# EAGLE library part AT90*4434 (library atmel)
MICROCONTROLLER Low-voltage (LS) 4 Kbytes FLASH 256 bytes SRAM 256 bytes EEPROM UART 8-channel 10 bit ADC

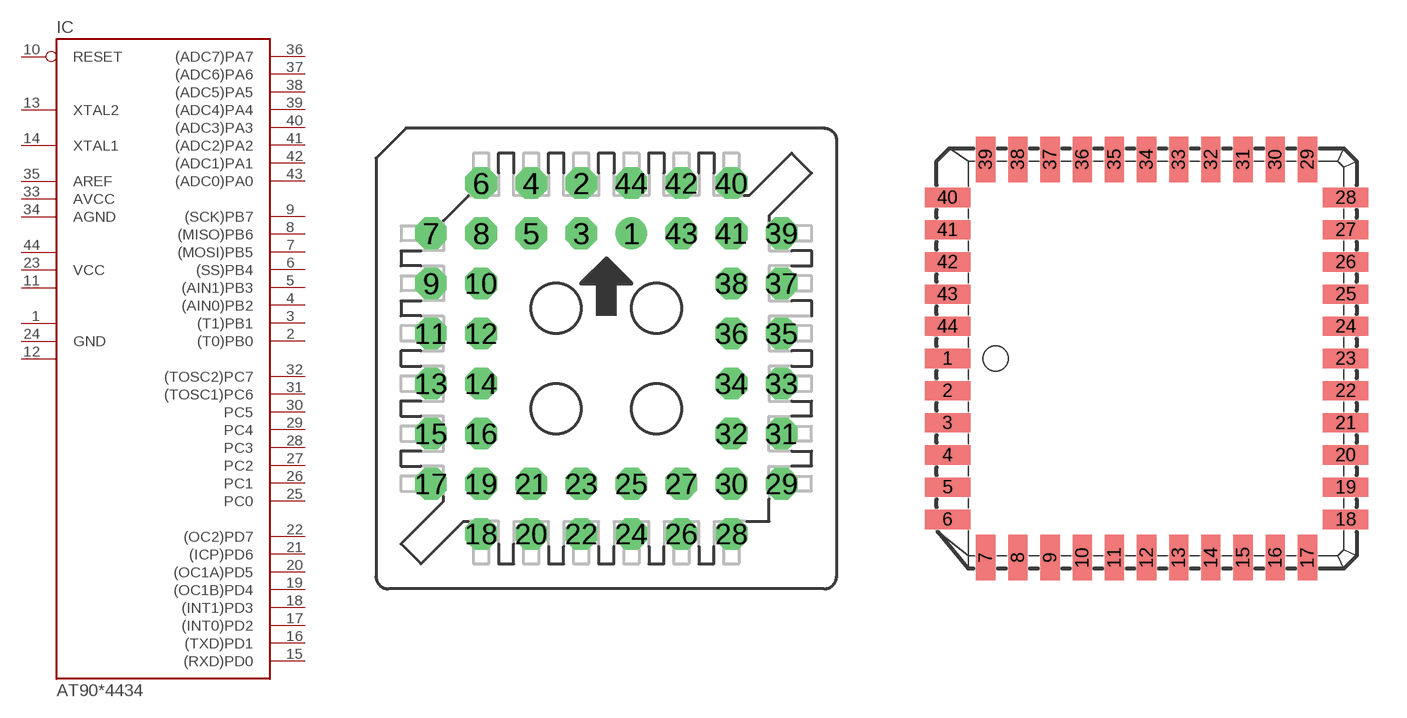
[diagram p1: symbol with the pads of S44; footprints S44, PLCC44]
Designator prefix IC

## AT90LS4434J-S (OC_FARNELL: unknown; OC_NEWARK: unknown), AT90S4434J-S (OC_FARNELL: unknown; OC_NEWARK: unknown)  [S44]
1  GND1  pwr
2  (T0)PB0
3  (T1)PB1
4  (AIN0)PB2
5  (AIN1)PB3
6  (SS)PB4
7  (MOSI)PB5
8  (MISO)PB6
9  (SCK)PB7
10  RESET  in
11  VCC2  pwr
12  GND2  pwr
13  XTAL2
14  XTAL1
15  (RXD)PD0
16  (TXD)PD1
17  (INT0)PD2
18  (INT1)PD3
19  (OC1B)PD4
20  (OC1A)PD5
21  (ICP)PD6
22  (OC2)PD7
23  VCC  pwr
24  GND  pwr
25  PC0
26  PC1
27  PC2
28  PC3
29  PC4
30  PC5
31  (TOSC1)PC6
32  (TOSC2)PC7
33  AVCC  pwr
34  AGND  pwr
35  AREF  pas
36  (ADC7)PA7
37  (ADC6)PA6
38  (ADC5)PA5
39  (ADC4)PA4
40  (ADC3)PA3
41  (ADC2)PA2
42  (ADC1)PA1
43  (ADC0)PA0
44  VCC1  pwr

## AT90LS4434J (OC_FARNELL: unknown; OC_NEWARK: unknown), AT90S4434J (OC_FARNELL: unknown; OC_NEWARK: unknown)  [PLCC44]
1  GND1  pwr
2  (T0)PB0
3  (T1)PB1
4  (AIN0)PB2
5  (AIN1)PB3
6  (SS)PB4
7  (MOSI)PB5
8  (MISO)PB6
9  (SCK)PB7
10  RESET  in
11  VCC1  pwr
12  GND2  pwr
13  XTAL2
14  XTAL1
15  (RXD)PD0
16  (TXD)PD1
17  (INT0)PD2
18  (INT1)PD3
19  (OC1B)PD4
20  (OC1A)PD5
21  (ICP)PD6
22  (OC2)PD7
23  VCC  pwr
24  GND  pwr
25  PC0
26  PC1
27  PC2
28  PC3
29  PC4
30  PC5
31  (TOSC1)PC6
32  (TOSC2)PC7
33  AVCC  pwr
34  AGND  pwr
35  AREF  pas
36  (ADC7)PA7
37  (ADC6)PA6
38  (ADC5)PA5
39  (ADC4)PA4
40  (ADC3)PA3
41  (ADC2)PA2
42  (ADC1)PA1
43  (ADC0)PA0
44  VCC2  pwr

## AT90LS4434J-SM (OC_FARNELL: unknown; OC_NEWARK: unknown), AT90S4434J-SM (OC_FARNELL: unknown; OC_NEWARK: unknown)  [PLCC-SM44]
Pads as for PLCC44

## AT904434A (OC_FARNELL: unknown; OC_NEWARK: unknown)  [TQFP44]
1  (MOSI)PB5
2  (MISO)PB6
3  (SCK)PB7
4  RESET  in
5  VCC  pwr
6  GND  pwr
7  XTAL2
8  XTAL1
9  (RXD)PD0
10  (TXD)PD1
11  (INT0)PD2
12  (INT1)PD3
13  (OC1B)PD4
14  (OC1A)PD5
15  (ICP)PD6
16  (OC2)PD7
17  VCC1  pwr
18  GND1  pwr
19  PC0
20  PC1
21  PC2
22  PC3
23  PC4
24  PC5
25  (TOSC1)PC6
26  (TOSC2)PC7
27  AVCC  pwr
28  AGND  pwr
29  AREF  pas
30  (ADC7)PA7
31  (ADC6)PA6
32  (ADC5)PA5
33  (ADC4)PA4
34  (ADC3)PA3
35  (ADC2)PA2
36  (ADC1)PA1
37  (ADC0)PA0
38  VCC2  pwr
39  GND2  pwr
40  (T0)PB0
41  (T1)PB1
42  (AIN0)PB2
43  (AIN1)PB3
44  (SS)PB4

## Footprint S44 (pad centres in mm)
Throughhole Plastic J-Leaded Chip Carrier Socket
drill 0.813 pad 1.6 round: 1 1.27,6.35
drill 0.813 pad 1.6 octagon: 2 -1.27,8.89; 3 -1.27,6.35; 4 -3.81,8.89; 5 -3.81,6.35; 6 -6.35,8.89; 7 -8.89,6.35; 8 -6.35,6.35; 9 -8.89,3.81; 10 -6.35,3.81; 11 -8.89,1.27; 12 -6.35,1.27; 13 -8.89,-1.27; 14 -6.35,-1.27; 15 -8.89,-3.81; 16 -6.35,-3.81; 17 -8.89,-6.35; 18 -6.35,-8.89; 19 -6.35,-6.35; 20 -3.81,-8.89; 21 -3.81,-6.35; 22 -1.27,-8.89; 23 -1.27,-6.35; 24 1.27,-8.89; 25 1.27,-6.35; 26 3.81,-8.89; 27 3.81,-6.35; 28 6.35,-8.89; 29 8.89,-6.35; 30 6.35,-6.35; 31 8.89,-3.81; 32 6.35,-3.81; 33 8.89,-1.27; 34 6.35,-1.27; 35 8.89,1.27; 36 6.35,1.27; 37 8.89,3.81; 38 6.35,3.81; 39 8.89,6.35; 40 6.35,8.89; 41 6.35,6.35; 42 3.81,8.89; 43 3.81,6.35; 44 1.27,8.89

## Footprint PLCC44 (pad centres in mm)
Plastic J-Leaded Chip Carrier
smd 1.8 x 0.76: 1 -7.86,0; 2 -7.86,-1.27; 3 -7.86,-2.54; 4 -7.86,-3.81; 5 -7.86,-5.08; 6 -7.86,-6.35; 18 7.86,-6.35; 19 7.86,-5.08; 20 7.86,-3.81; 21 7.86,-2.54; 22 7.86,-1.27; 23 7.86,0; 24 7.86,1.27; 25 7.86,2.54; 26 7.86,3.81; 27 7.86,5.08; 28 7.86,6.35; 40 -7.86,6.35; 41 -7.86,5.08; 42 -7.86,3.81; 43 -7.86,2.54; 44 -7.86,1.27
smd 0.76 x 1.8: 7 -6.35,-7.86; 8 -5.08,-7.86; 9 -3.81,-7.86; 10 -2.54,-7.86; 11 -1.27,-7.86; 12 0,-7.86; 13 1.27,-7.86; 14 2.54,-7.86; 15 3.81,-7.86; 16 5.08,-7.86; 17 6.35,-7.86; 29 6.35,7.86; 30 5.08,7.86; 31 3.81,7.86; 32 2.54,7.86; 33 1.27,7.86; 34 0,7.86; 35 -1.27,7.86; 36 -2.54,7.86; 37 -3.81,7.86; 38 -5.08,7.86; 39 -6.35,7.86

## Footprint PLCC-SM44 (pad centres in mm)
SMD Plastic J-Leaded Chip Carrier Socket
smd 2.591 x 0.66: 1 -8.89,0; 2 -8.89,-1.27; 3 -8.89,-2.54; 4 -8.89,-3.81; 5 -8.89,-5.08; 6 -8.89,-6.35; 18 8.89,-6.35; 19 8.89,-5.08; 20 8.89,-3.81; 21 8.89,-2.54; 22 8.89,-1.27; 23 8.89,0; 24 8.89,1.27; 25 8.89,2.54; 26 8.89,3.81; 27 8.89,5.08; 28 8.89,6.35; 40 -8.89,6.35; 41 -8.89,5.08; 42 -8.89,3.81; 43 -8.89,2.54; 44 -8.89,1.27
smd 0.66 x 2.591: 7 -6.35,-8.89; 8 -5.08,-8.89; 9 -3.81,-8.89; 10 -2.54,-8.89; 11 -1.27,-8.89; 12 0,-8.89; 13 1.27,-8.89; 14 2.54,-8.89; 15 3.81,-8.89; 16 5.08,-8.89; 17 6.35,-8.89; 29 6.35,8.89; 30 5.08,8.89; 31 3.81,8.89; 32 2.54,8.89; 33 1.27,8.89; 34 0,9.017; 35 -1.27,8.89; 36 -2.54,8.89; 37 -3.81,8.89; 38 -5.08,8.89; 39 -6.35,8.89

## Footprint TQFP44 (pad centres in mm)
44-lead Thin Quad Flat Package
smd 1.5 x 0.5: 1 -5.8,4; 2 -5.8,3.2; 3 -5.8,2.4; 4 -5.8,1.6; 5 -5.8,0.8; 6 -5.8,0; 7 -5.8,-0.8; 8 -5.8,-1.6; 9 -5.8,-2.4; 10 -5.8,-3.2; 11 -5.8,-4; 23 5.8,-4; 24 5.8,-3.2; 25 5.8,-2.4; 26 5.8,-1.6; 27 5.8,-0.8; 28 5.8,0; 29 5.8,0.8; 30 5.8,1.6; 31 5.8,2.4; 32 5.8,3.2; 33 5.8,4
smd 0.5 x 1.5: 12 -4,-5.8; 13 -3.2,-5.8; 14 -2.4,-5.8; 15 -1.6,-5.8; 16 -0.8,-5.8; 17 0,-5.8; 18 0.8,-5.8; 19 1.6,-5.8; 20 2.4,-5.8; 21 3.2,-5.8; 22 4,-5.8; 34 4,5.8; 35 3.2,5.8; 36 2.4,5.8; 37 1.6,5.8; 38 0.8,5.8; 39 0,5.8; 40 -0.8,5.8; 41 -1.6,5.8; 42 -2.4,5.8; 43 -3.2,5.8; 44 -4,5.8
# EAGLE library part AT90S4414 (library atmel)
MICROCONTROLLER 4 Kbytes FLASH 256 bytes SRAM 256 bytes EEPROM UART

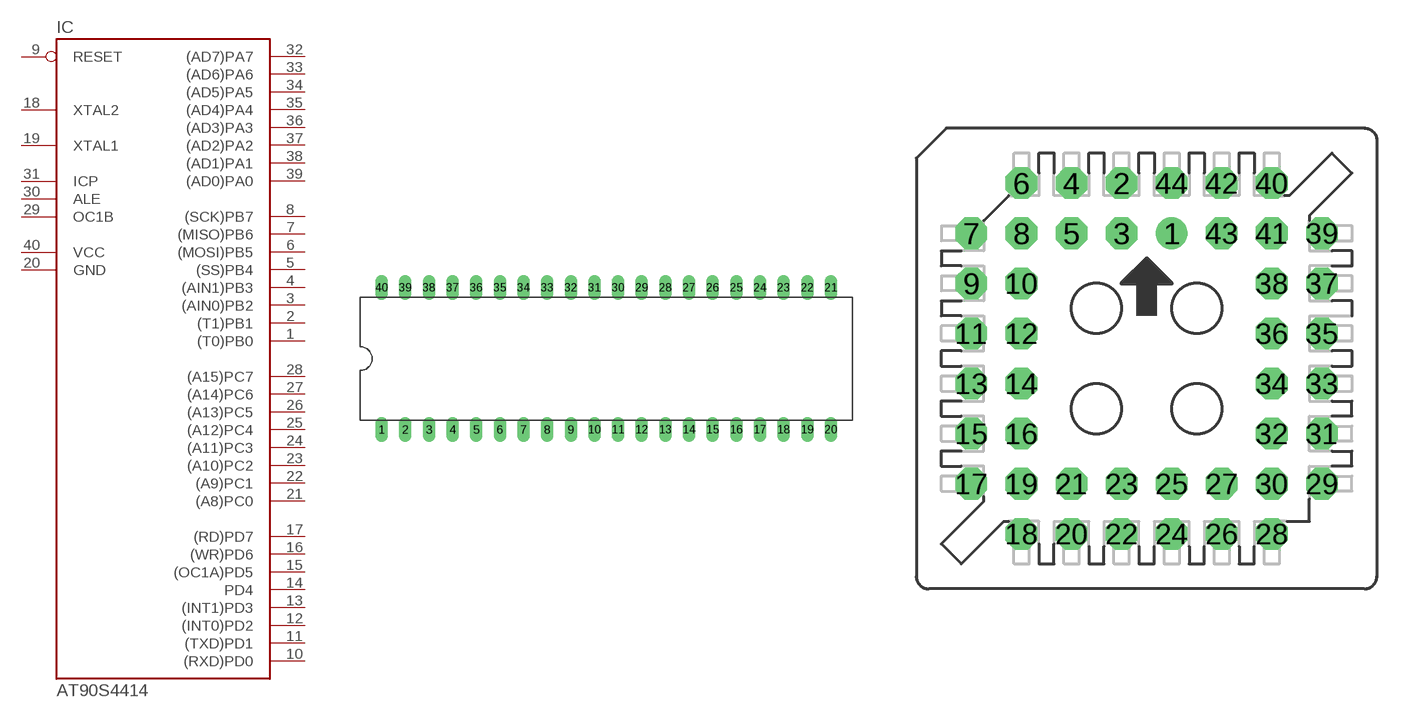
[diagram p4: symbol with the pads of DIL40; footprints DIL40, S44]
Designator prefix IC

## AT90S4414P (OC_FARNELL: unknown; OC_NEWARK: unknown)  [DIL40]
1  (T0)PB0
2  (T1)PB1
3  (AIN0)PB2
4  (AIN1)PB3
5  (SS)PB4
6  (MOSI)PB5
7  (MISO)PB6
8  (SCK)PB7
9  RESET  in
10  (RXD)PD0
11  (TXD)PD1
12  (INT0)PD2
13  (INT1)PD3
14  PD4
15  (OC1A)PD5
16  (WR)PD6
17  (RD)PD7
18  XTAL2
19  XTAL1
20  GND  pwr
21  (A8)PC0
22  (A9)PC1
23  (A10)PC2
24  (A11)PC3
25  (A12)PC4
26  (A13)PC5
27  (A14)PC6
28  (A15)PC7
29  OC1B
30  ALE
31  ICP
32  (AD7)PA7
33  (AD6)PA6
34  (AD5)PA5
35  (AD4)PA4
36  (AD3)PA3
37  (AD2)PA2
38  (AD1)PA1
39  (AD0)PA0
40  VCC  pwr

## AT90S4414J1 (OC_FARNELL: unknown; OC_NEWARK: unknown)  [S44]
2  (T0)PB0
3  (T1)PB1
4  (AIN0)PB2
5  (AIN1)PB3
6  (SS)PB4
7  (MOSI)PB5
8  (MISO)PB6
9  (SCK)PB7
10  RESET  in
11  (RXD)PD0
13  (TXD)PD1
14  (INT0)PD2
15  (INT1)PD3
16  PD4
17  (OC1A)PD5
18  (WR)PD6
19  (RD)PD7
20  XTAL2
21  XTAL1
22  GND  pwr
24  (A8)PC0
25  (A9)PC1
26  (A10)PC2
27  (A11)PC3
28  (A12)PC4
29  (A13)PC5
30  (A14)PC6
31  (A15)PC7
32  OC1B
33  ALE
35  ICP
36  (AD7)PA7
37  (AD6)PA6
38  (AD5)PA5
39  (AD4)PA4
40  (AD3)PA3
41  (AD2)PA2
42  (AD1)PA1
43  (AD0)PA0
44  VCC  pwr

## AT90S4414J2 (OC_FARNELL: unknown; OC_NEWARK: unknown)  [PLCC44]
Pads as for S44

## AT90S4414J3 (OC_FARNELL: unknown; OC_NEWARK: unknown)  [PLCC-SM44]
Pads as for S44

## AT90S4414A (OC_FARNELL: unknown; OC_NEWARK: unknown)  [TQFP44]
1  (MOSI)PB5
2  (MISO)PB6
3  (SCK)PB7
4  RESET  in
5  (RXD)PD0
7  (TXD)PD1
8  (INT0)PD2
9  (INT1)PD3
10  PD4
11  (OC1A)PD5
12  (WR)PD6
13  (RD)PD7
14  XTAL2
15  XTAL1
16  GND  pwr
18  (A8)PC0
19  (A9)PC1
20  (A10)PC2
21  (A11)PC3
22  (A12)PC4
23  (A13)PC5
24  (A14)PC6
25  (A15)PC7
26  OC1B
27  ALE
29  ICP
30  (AD7)PA7
31  (AD6)PA6
32  (AD5)PA5
33  (AD4)PA4
34  (AD3)PA3
35  (AD2)PA2
36  (AD1)PA1
37  (AD0)PA0
38  VCC  pwr
40  (T0)PB0
41  (T1)PB1
42  (AIN0)PB2
43  (AIN1)PB3
44  (SS)PB4

## Footprint DIL40 (pad centres in mm)
Dual In Line
drill 0.813 long: 1 -24.13,-7.62; 2 -21.59,-7.62; 3 -19.05,-7.62; 4 -16.51,-7.62; 5 -13.97,-7.62; 6 -11.43,-7.62; 7 -8.89,-7.62; 8 -6.35,-7.62; 9 -3.81,-7.62; 10 -1.27,-7.62; 11 1.27,-7.62; 12 3.81,-7.62; 13 6.35,-7.62; 14 8.89,-7.62; 15 11.43,-7.62; 16 13.97,-7.62; 17 16.51,-7.62; 18 19.05,-7.62; 19 21.59,-7.62; 20 24.13,-7.62; 21 24.13,7.62; 22 21.59,7.62; 23 19.05,7.62; 24 16.51,7.62; 25 13.97,7.62; 26 11.43,7.62; 27 8.89,7.62; 28 6.35,7.62; 29 3.81,7.62; 30 1.27,7.62; 31 -1.27,7.62; 32 -3.81,7.62; 33 -6.35,7.62; 34 -8.89,7.62; 35 -11.43,7.62; 36 -13.97,7.62; 37 -16.51,7.62; 38 -19.05,7.62; 39 -21.59,7.62; 40 -24.13,7.62

## Footprint S44 (pad centres in mm)
Throughhole Plastic J-Leaded Chip Carrier Socket
drill 0.813 pad 1.6 round: 1 1.27,6.35
drill 0.813 pad 1.6 octagon: 2 -1.27,8.89; 3 -1.27,6.35; 4 -3.81,8.89; 5 -3.81,6.35; 6 -6.35,8.89; 7 -8.89,6.35; 8 -6.35,6.35; 9 -8.89,3.81; 10 -6.35,3.81; 11 -8.89,1.27; 12 -6.35,1.27; 13 -8.89,-1.27; 14 -6.35,-1.27; 15 -8.89,-3.81; 16 -6.35,-3.81; 17 -8.89,-6.35; 18 -6.35,-8.89; 19 -6.35,-6.35; 20 -3.81,-8.89; 21 -3.81,-6.35; 22 -1.27,-8.89; 23 -1.27,-6.35; 24 1.27,-8.89; 25 1.27,-6.35; 26 3.81,-8.89; 27 3.81,-6.35; 28 6.35,-8.89; 29 8.89,-6.35; 30 6.35,-6.35; 31 8.89,-3.81; 32 6.35,-3.81; 33 8.89,-1.27; 34 6.35,-1.27; 35 8.89,1.27; 36 6.35,1.27; 37 8.89,3.81; 38 6.35,3.81; 39 8.89,6.35; 40 6.35,8.89; 41 6.35,6.35; 42 3.81,8.89; 43 3.81,6.35; 44 1.27,8.89

## Footprint PLCC44 (pad centres in mm)
Plastic J-Leaded Chip Carrier
smd 1.8 x 0.76: 1 -7.86,0; 2 -7.86,-1.27; 3 -7.86,-2.54; 4 -7.86,-3.81; 5 -7.86,-5.08; 6 -7.86,-6.35; 18 7.86,-6.35; 19 7.86,-5.08; 20 7.86,-3.81; 21 7.86,-2.54; 22 7.86,-1.27; 23 7.86,0; 24 7.86,1.27; 25 7.86,2.54; 26 7.86,3.81; 27 7.86,5.08; 28 7.86,6.35; 40 -7.86,6.35; 41 -7.86,5.08; 42 -7.86,3.81; 43 -7.86,2.54; 44 -7.86,1.27
smd 0.76 x 1.8: 7 -6.35,-7.86; 8 -5.08,-7.86; 9 -3.81,-7.86; 10 -2.54,-7.86; 11 -1.27,-7.86; 12 0,-7.86; 13 1.27,-7.86; 14 2.54,-7.86; 15 3.81,-7.86; 16 5.08,-7.86; 17 6.35,-7.86; 29 6.35,7.86; 30 5.08,7.86; 31 3.81,7.86; 32 2.54,7.86; 33 1.27,7.86; 34 0,7.86; 35 -1.27,7.86; 36 -2.54,7.86; 37 -3.81,7.86; 38 -5.08,7.86; 39 -6.35,7.86

## Footprint PLCC-SM44 (pad centres in mm)
SMD Plastic J-Leaded Chip Carrier Socket
smd 2.591 x 0.66: 1 -8.89,0; 2 -8.89,-1.27; 3 -8.89,-2.54; 4 -8.89,-3.81; 5 -8.89,-5.08; 6 -8.89,-6.35; 18 8.89,-6.35; 19 8.89,-5.08; 20 8.89,-3.81; 21 8.89,-2.54; 22 8.89,-1.27; 23 8.89,0; 24 8.89,1.27; 25 8.89,2.54; 26 8.89,3.81; 27 8.89,5.08; 28 8.89,6.35; 40 -8.89,6.35; 41 -8.89,5.08; 42 -8.89,3.81; 43 -8.89,2.54; 44 -8.89,1.27
smd 0.66 x 2.591: 7 -6.35,-8.89; 8 -5.08,-8.89; 9 -3.81,-8.89; 10 -2.54,-8.89; 11 -1.27,-8.89; 12 0,-8.89; 13 1.27,-8.89; 14 2.54,-8.89; 15 3.81,-8.89; 16 5.08,-8.89; 17 6.35,-8.89; 29 6.35,8.89; 30 5.08,8.89; 31 3.81,8.89; 32 2.54,8.89; 33 1.27,8.89; 34 0,9.017; 35 -1.27,8.89; 36 -2.54,8.89; 37 -3.81,8.89; 38 -5.08,8.89; 39 -6.35,8.89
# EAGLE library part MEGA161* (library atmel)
MICROCONTROLLER 16 Kbytes FLASH 512 bytes EEPROM 1 Kbytes SRAM dual UART hardware multiplier Source: avr.lbr

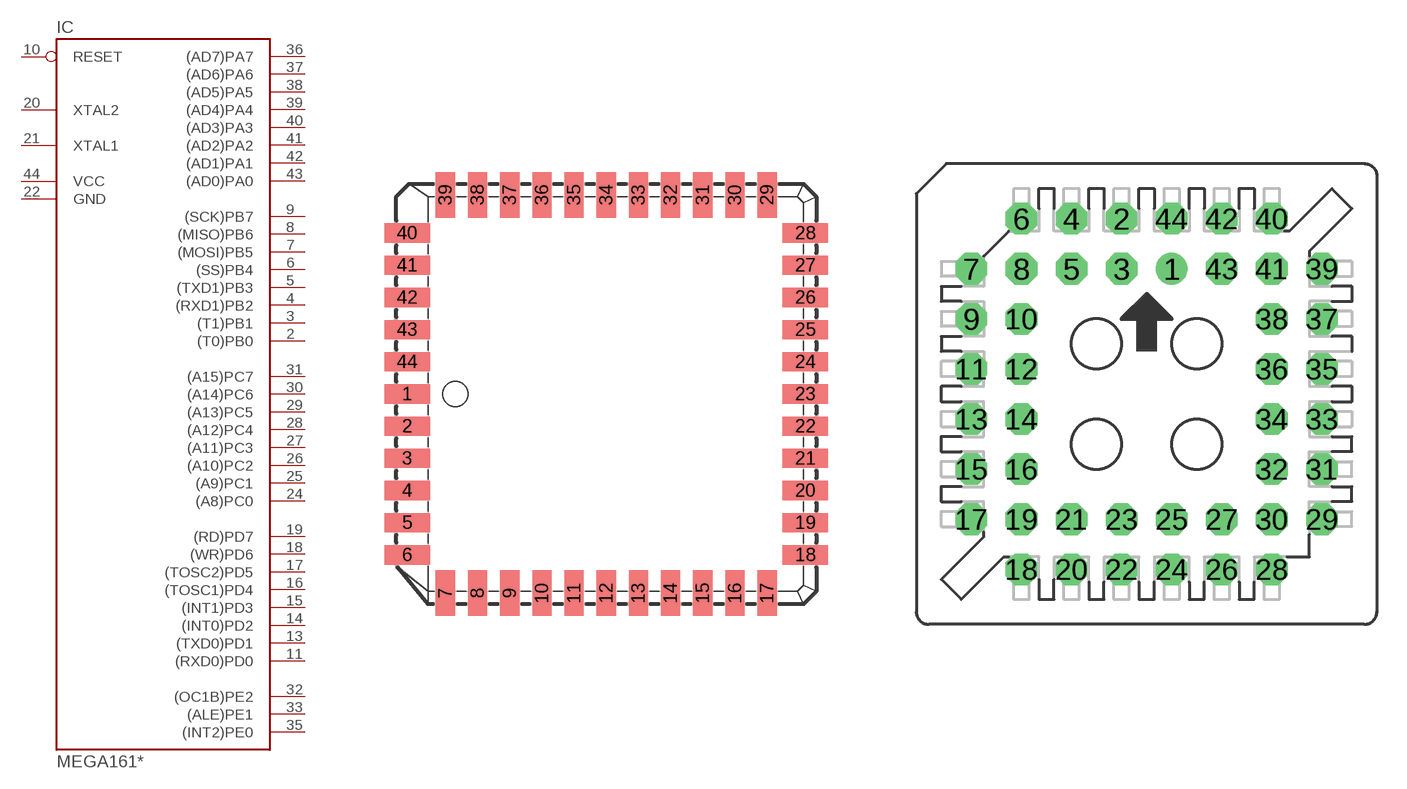
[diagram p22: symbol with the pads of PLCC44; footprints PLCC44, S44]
Designator prefix IC

## MEGA161J (OC_FARNELL: unknown; OC_NEWARK: unknown), MEGA161LJ (OC_FARNELL: unknown; OC_NEWARK: unknown)  [PLCC44]
1  NC1  nc
2  (T0)PB0
3  (T1)PB1
4  (RXD1)PB2
5  (TXD1)PB3
6  (SS)PB4
7  (MOSI)PB5
8  (MISO)PB6
9  (SCK)PB7
10  RESET  in
11  (RXD0)PD0
12  NC2  nc
13  (TXD0)PD1
14  (INT0)PD2
15  (INT1)PD3
16  (TOSC1)PD4
17  (TOSC2)PD5
18  (WR)PD6
19  (RD)PD7
20  XTAL2  in
21  XTAL1  in
22  GND  pwr
23  NC3  nc
24  (A8)PC0
25  (A9)PC1
26  (A10)PC2
27  (A11)PC3
28  (A12)PC4
29  (A13)PC5
30  (A14)PC6
31  (A15)PC7
32  (OC1B)PE2
33  (ALE)PE1
34  NC4  nc
35  (INT2)PE0
36  (AD7)PA7
37  (AD6)PA6
38  (AD5)PA5
39  (AD4)PA4
40  (AD3)PA3
41  (AD2)PA2
42  (AD1)PA1
43  (AD0)PA0
44  VCC  pwr

## MEGA161J-S (OC_FARNELL: unknown; OC_NEWARK: unknown)  [S44]
Pads as for PLCC44

## MEGA161J-SM (OC_FARNELL: unknown; OC_NEWARK: unknown)  [PLCC-SM44]
Pads as for PLCC44

## MEGA161A (MPN: ATMEGA16-16AU; OC_FARNELL: 9171134; OC_NEWARK: 96K6515)  [TQFP44]
1  (MOSI)PB5
2  (MISO)PB6
3  (SCK)PB7
4  RESET  in
5  (RXD0)PD0
6  NC1  nc
7  (TXD0)PD1
8  (INT0)PD2
9  (INT1)PD3
10  (TOSC1)PD4
11  (TOSC2)PD5
12  (WR)PD6
13  (RD)PD7
14  XTAL2  in
15  XTAL1  in
16  GND  pwr
17  NC2  nc
18  (A8)PC0
19  (A9)PC1
20  (A10)PC2
21  (A11)PC3
22  (A12)PC4
23  (A13)PC5
24  (A14)PC6
25  (A15)PC7
26  (OC1B)PE2
27  (ALE)PE1
28  NC3  nc
29  (INT2)PE0
30  (AD7)PA7
31  (AD6)PA6
32  (AD5)PA5
33  (AD4)PA4
34  (AD3)PA3
35  (AD2)PA2
36  (AD1)PA1
37  (AD0)PA0
38  VCC  pwr
39  NC4  nc
40  (T0)PB0
41  (T1)PB1
42  (RXD1)PB2
43  (TXD1)PB3
44  (SS)PB4

## Footprint PLCC44 (pad centres in mm)
Plastic J-Leaded Chip Carrier
smd 1.8 x 0.76: 1 -7.86,0; 2 -7.86,-1.27; 3 -7.86,-2.54; 4 -7.86,-3.81; 5 -7.86,-5.08; 6 -7.86,-6.35; 18 7.86,-6.35; 19 7.86,-5.08; 20 7.86,-3.81; 21 7.86,-2.54; 22 7.86,-1.27; 23 7.86,0; 24 7.86,1.27; 25 7.86,2.54; 26 7.86,3.81; 27 7.86,5.08; 28 7.86,6.35; 40 -7.86,6.35; 41 -7.86,5.08; 42 -7.86,3.81; 43 -7.86,2.54; 44 -7.86,1.27
smd 0.76 x 1.8: 7 -6.35,-7.86; 8 -5.08,-7.86; 9 -3.81,-7.86; 10 -2.54,-7.86; 11 -1.27,-7.86; 12 0,-7.86; 13 1.27,-7.86; 14 2.54,-7.86; 15 3.81,-7.86; 16 5.08,-7.86; 17 6.35,-7.86; 29 6.35,7.86; 30 5.08,7.86; 31 3.81,7.86; 32 2.54,7.86; 33 1.27,7.86; 34 0,7.86; 35 -1.27,7.86; 36 -2.54,7.86; 37 -3.81,7.86; 38 -5.08,7.86; 39 -6.35,7.86

## Footprint S44 (pad centres in mm)
Throughhole Plastic J-Leaded Chip Carrier Socket
drill 0.813 pad 1.6 round: 1 1.27,6.35
drill 0.813 pad 1.6 octagon: 2 -1.27,8.89; 3 -1.27,6.35; 4 -3.81,8.89; 5 -3.81,6.35; 6 -6.35,8.89; 7 -8.89,6.35; 8 -6.35,6.35; 9 -8.89,3.81; 10 -6.35,3.81; 11 -8.89,1.27; 12 -6.35,1.27; 13 -8.89,-1.27; 14 -6.35,-1.27; 15 -8.89,-3.81; 16 -6.35,-3.81; 17 -8.89,-6.35; 18 -6.35,-8.89; 19 -6.35,-6.35; 20 -3.81,-8.89; 21 -3.81,-6.35; 22 -1.27,-8.89; 23 -1.27,-6.35; 24 1.27,-8.89; 25 1.27,-6.35; 26 3.81,-8.89; 27 3.81,-6.35; 28 6.35,-8.89; 29 8.89,-6.35; 30 6.35,-6.35; 31 8.89,-3.81; 32 6.35,-3.81; 33 8.89,-1.27; 34 6.35,-1.27; 35 8.89,1.27; 36 6.35,1.27; 37 8.89,3.81; 38 6.35,3.81; 39 8.89,6.35; 40 6.35,8.89; 41 6.35,6.35; 42 3.81,8.89; 43 3.81,6.35; 44 1.27,8.89

## Footprint PLCC-SM44 (pad centres in mm)
SMD Plastic J-Leaded Chip Carrier Socket
smd 2.591 x 0.66: 1 -8.89,0; 2 -8.89,-1.27; 3 -8.89,-2.54; 4 -8.89,-3.81; 5 -8.89,-5.08; 6 -8.89,-6.35; 18 8.89,-6.35; 19 8.89,-5.08; 20 8.89,-3.81; 21 8.89,-2.54; 22 8.89,-1.27; 23 8.89,0; 24 8.89,1.27; 25 8.89,2.54; 26 8.89,3.81; 27 8.89,5.08; 28 8.89,6.35; 40 -8.89,6.35; 41 -8.89,5.08; 42 -8.89,3.81; 43 -8.89,2.54; 44 -8.89,1.27
smd 0.66 x 2.591: 7 -6.35,-8.89; 8 -5.08,-8.89; 9 -3.81,-8.89; 10 -2.54,-8.89; 11 -1.27,-8.89; 12 0,-8.89; 13 1.27,-8.89; 14 2.54,-8.89; 15 3.81,-8.89; 16 5.08,-8.89; 17 6.35,-8.89; 29 6.35,8.89; 30 5.08,8.89; 31 3.81,8.89; 32 2.54,8.89; 33 1.27,8.89; 34 0,9.017; 35 -1.27,8.89; 36 -2.54,8.89; 37 -3.81,8.89; 38 -5.08,8.89; 39 -6.35,8.89

## Footprint TQFP44 (pad centres in mm)
44-lead Thin Quad Flat Package
smd 1.5 x 0.5: 1 -5.8,4; 2 -5.8,3.2; 3 -5.8,2.4; 4 -5.8,1.6; 5 -5.8,0.8; 6 -5.8,0; 7 -5.8,-0.8; 8 -5.8,-1.6; 9 -5.8,-2.4; 10 -5.8,-3.2; 11 -5.8,-4; 23 5.8,-4; 24 5.8,-3.2; 25 5.8,-2.4; 26 5.8,-1.6; 27 5.8,-0.8; 28 5.8,0; 29 5.8,0.8; 30 5.8,1.6; 31 5.8,2.4; 32 5.8,3.2; 33 5.8,4
smd 0.5 x 1.5: 12 -4,-5.8; 13 -3.2,-5.8; 14 -2.4,-5.8; 15 -1.6,-5.8; 16 -0.8,-5.8; 17 0,-5.8; 18 0.8,-5.8; 19 1.6,-5.8; 20 2.4,-5.8; 21 3.2,-5.8; 22 4,-5.8; 34 4,5.8; 35 3.2,5.8; 36 2.4,5.8; 37 1.6,5.8; 38 0.8,5.8; 39 0,5.8; 40 -0.8,5.8; 41 -1.6,5.8; 42 -2.4,5.8; 43 -3.2,5.8; 44 -4,5.8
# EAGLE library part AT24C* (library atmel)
2-wire serial EEPROM

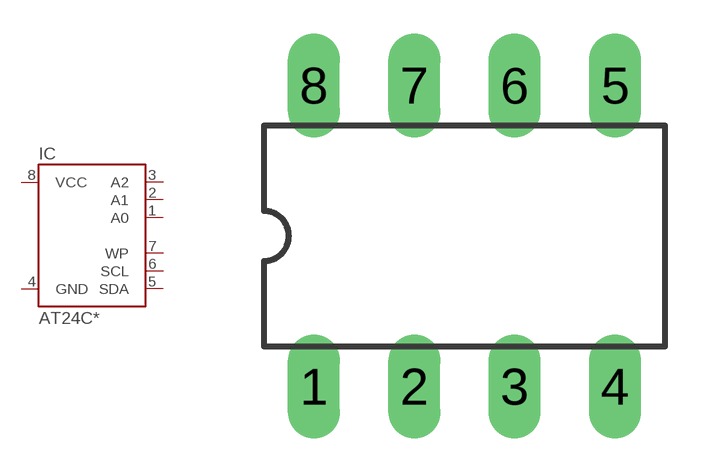
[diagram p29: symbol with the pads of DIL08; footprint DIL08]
Designator prefix IC

## AT24CP (MPN: AT24C1024BW-SH-B; OC_FARNELL: 1362646; OC_NEWARK: 03P2044)  [DIL08]
1  A0  in
2  A1  in
3  A2  in
4  GND  pwr
5  SDA
6  SCL
7  WP  in
8  VCC  pwr

## Footprint DIL08 (pad centres in mm)
Dual In Line
drill 0.813 long: 1 -3.81,-3.81; 2 -1.27,-3.81; 3 1.27,-3.81; 4 3.81,-3.81; 5 3.81,3.81; 6 1.27,3.81; 7 -1.27,3.81; 8 -3.81,3.81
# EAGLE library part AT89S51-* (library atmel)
8-bit Microcontroller with 4K BytesIn-System Programmable Flash Source: http://www.atmel.com/dyn/resources/prod_documents/doc2487.pdf

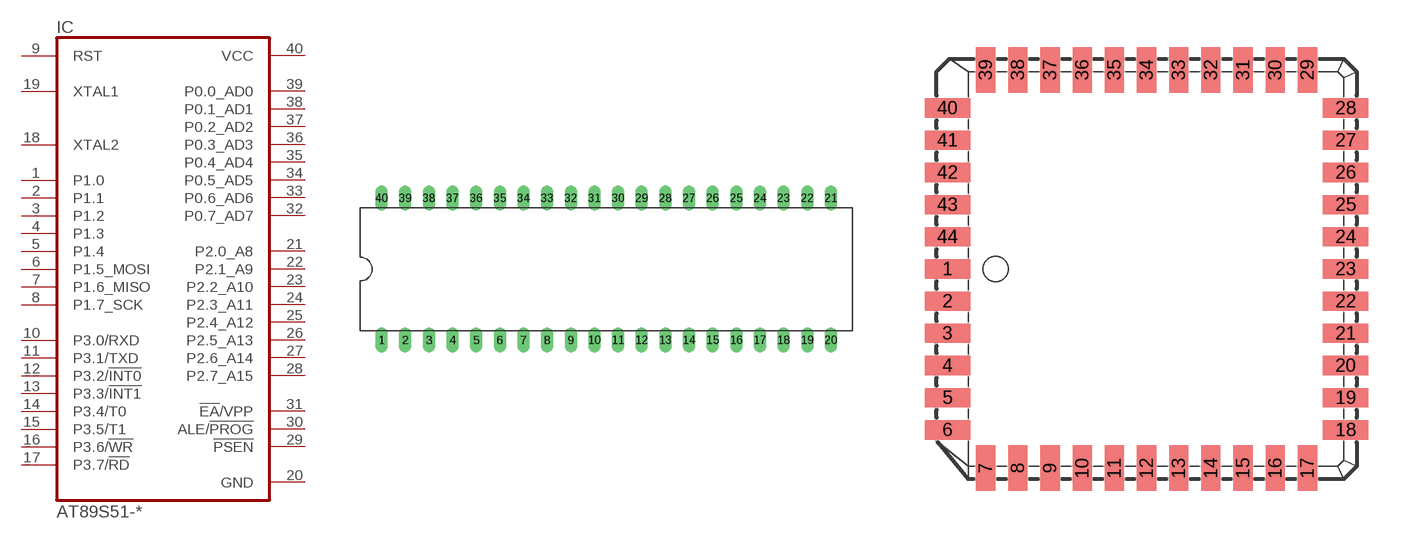
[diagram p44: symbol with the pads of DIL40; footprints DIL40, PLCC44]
Designator prefix IC

## AT89S51-24P (MPN: AT89S51-24PU; OC_FARNELL: 1095739; OC_NEWARK: 96K6578), AT89S51-33P (MPN: AT89S51-24PU; OC_FARNELL: 1095739; OC_NEWARK: 96K6578)  [DIL40]
1  P1.0
2  P1.1
3  P1.2
4  P1.3
5  P1.4
6  P1.5_MOSI
7  P1.6_MISO
8  P1.7_SCK
9  RST  in
10  P3.0/RXD
11  P3.1/TXD
12  P3.2/!INT0
13  P3.3/!INT1
14  P3.4/T0
15  P3.5/T1
16  P3.6/!WR
17  P3.7/!RD
18  XTAL2  in
19  XTAL1  in
20  GND  pwr
21  P2.0_A8
22  P2.1_A9
23  P2.2_A10
24  P2.3_A11
25  P2.4_A12
26  P2.5_A13
27  P2.6_A14
28  P2.7_A15
29  !PSEN  out
30  ALE/!PROG  out
31  !EA!/VPP  in
32  P0.7_AD7
33  P0.6_AD6
34  P0.5_AD5
35  P0.4_AD4
36  P0.3_AD3
37  P0.2_AD2
38  P0.1_AD1
39  P0.0_AD0
40  VCC  pwr

## AT89S51-24J (MPN: AT89S51-24JU; OC_FARNELL: 1095738; OC_NEWARK: 96K6577), AT89S51-33J (OC_FARNELL: 1095738; OC_NEWARK: unknown)  [PLCC44]
2  P1.0
3  P1.1
4  P1.2
5  P1.3
6  P1.4
7  P1.5_MOSI
8  P1.6_MISO
9  P1.7_SCK
10  RST  in
11  P3.0/RXD
13  P3.1/TXD
14  P3.2/!INT0
15  P3.3/!INT1
16  P3.4/T0
17  P3.5/T1
18  P3.6/!WR
19  P3.7/!RD
20  XTAL2  in
21  XTAL1  in
22  GND  pwr
24  P2.0_A8
25  P2.1_A9
26  P2.2_A10
27  P2.3_A11
28  P2.4_A12
29  P2.5_A13
30  P2.6_A14
31  P2.7_A15
32  !PSEN  out
33  ALE/!PROG  out
35  !EA!/VPP  in
36  P0.7_AD7
37  P0.6_AD6
38  P0.5_AD5
39  P0.4_AD4
40  P0.3_AD3
41  P0.2_AD2
42  P0.1_AD1
43  P0.0_AD0
44  VCC  pwr

## AT89S51-S (OC_FARNELL: unknown; OC_NEWARK: unknown)  [S44]
Pads as for PLCC44

## Footprint DIL40 (pad centres in mm)
Dual In Line
drill 0.813 long: 1 -24.13,-7.62; 2 -21.59,-7.62; 3 -19.05,-7.62; 4 -16.51,-7.62; 5 -13.97,-7.62; 6 -11.43,-7.62; 7 -8.89,-7.62; 8 -6.35,-7.62; 9 -3.81,-7.62; 10 -1.27,-7.62; 11 1.27,-7.62; 12 3.81,-7.62; 13 6.35,-7.62; 14 8.89,-7.62; 15 11.43,-7.62; 16 13.97,-7.62; 17 16.51,-7.62; 18 19.05,-7.62; 19 21.59,-7.62; 20 24.13,-7.62; 21 24.13,7.62; 22 21.59,7.62; 23 19.05,7.62; 24 16.51,7.62; 25 13.97,7.62; 26 11.43,7.62; 27 8.89,7.62; 28 6.35,7.62; 29 3.81,7.62; 30 1.27,7.62; 31 -1.27,7.62; 32 -3.81,7.62; 33 -6.35,7.62; 34 -8.89,7.62; 35 -11.43,7.62; 36 -13.97,7.62; 37 -16.51,7.62; 38 -19.05,7.62; 39 -21.59,7.62; 40 -24.13,7.62

## Footprint PLCC44 (pad centres in mm)
Plastic J-Leaded Chip Carrier
smd 1.8 x 0.76: 1 -7.86,0; 2 -7.86,-1.27; 3 -7.86,-2.54; 4 -7.86,-3.81; 5 -7.86,-5.08; 6 -7.86,-6.35; 18 7.86,-6.35; 19 7.86,-5.08; 20 7.86,-3.81; 21 7.86,-2.54; 22 7.86,-1.27; 23 7.86,0; 24 7.86,1.27; 25 7.86,2.54; 26 7.86,3.81; 27 7.86,5.08; 28 7.86,6.35; 40 -7.86,6.35; 41 -7.86,5.08; 42 -7.86,3.81; 43 -7.86,2.54; 44 -7.86,1.27
smd 0.76 x 1.8: 7 -6.35,-7.86; 8 -5.08,-7.86; 9 -3.81,-7.86; 10 -2.54,-7.86; 11 -1.27,-7.86; 12 0,-7.86; 13 1.27,-7.86; 14 2.54,-7.86; 15 3.81,-7.86; 16 5.08,-7.86; 17 6.35,-7.86; 29 6.35,7.86; 30 5.08,7.86; 31 3.81,7.86; 32 2.54,7.86; 33 1.27,7.86; 34 0,7.86; 35 -1.27,7.86; 36 -2.54,7.86; 37 -3.81,7.86; 38 -5.08,7.86; 39 -6.35,7.86

## Footprint S44 (pad centres in mm)
Throughhole Plastic J-Leaded Chip Carrier Socket
drill 0.813 pad 1.6 round: 1 1.27,6.35
drill 0.813 pad 1.6 octagon: 2 -1.27,8.89; 3 -1.27,6.35; 4 -3.81,8.89; 5 -3.81,6.35; 6 -6.35,8.89; 7 -8.89,6.35; 8 -6.35,6.35; 9 -8.89,3.81; 10 -6.35,3.81; 11 -8.89,1.27; 12 -6.35,1.27; 13 -8.89,-1.27; 14 -6.35,-1.27; 15 -8.89,-3.81; 16 -6.35,-3.81; 17 -8.89,-6.35; 18 -6.35,-8.89; 19 -6.35,-6.35; 20 -3.81,-8.89; 21 -3.81,-6.35; 22 -1.27,-8.89; 23 -1.27,-6.35; 24 1.27,-8.89; 25 1.27,-6.35; 26 3.81,-8.89; 27 3.81,-6.35; 28 6.35,-8.89; 29 8.89,-6.35; 30 6.35,-6.35; 31 8.89,-3.81; 32 6.35,-3.81; 33 8.89,-1.27; 34 6.35,-1.27; 35 8.89,1.27; 36 6.35,1.27; 37 8.89,3.81; 38 6.35,3.81; 39 8.89,6.35; 40 6.35,8.89; 41 6.35,6.35; 42 3.81,8.89; 43 3.81,6.35; 44 1.27,8.89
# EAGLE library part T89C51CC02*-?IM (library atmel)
Enhanced 8-bit Microcontroller with CAN Controller and Flash 80C51 Core Architecture Source: http://www.atmel.com/dyn/resources/prod_documents/doc4126.

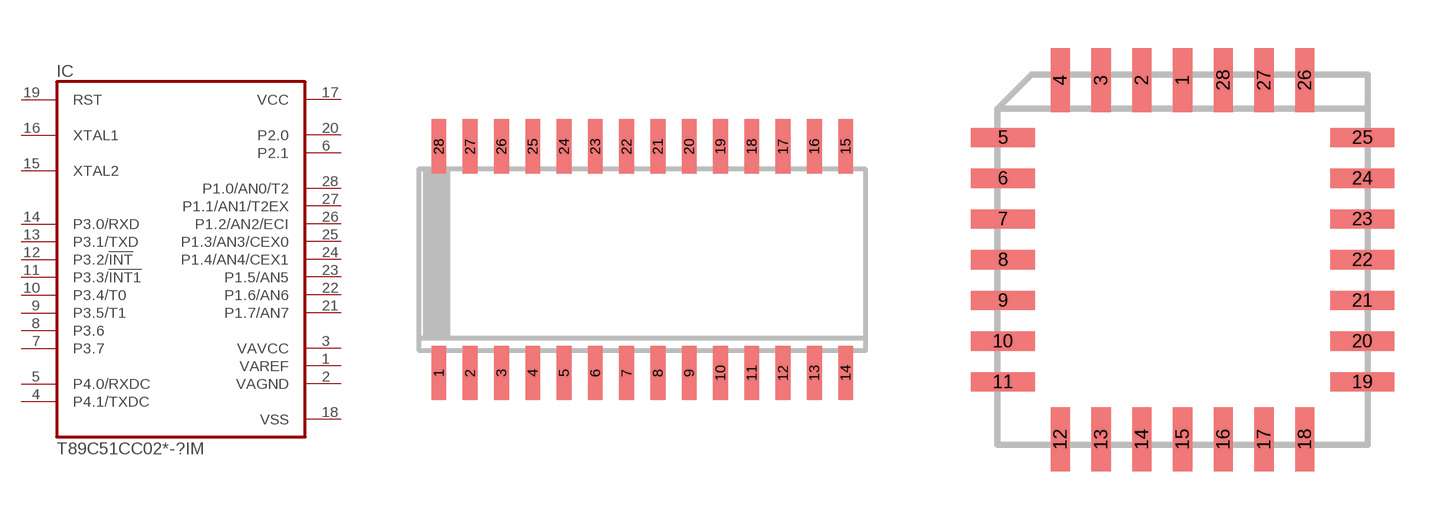
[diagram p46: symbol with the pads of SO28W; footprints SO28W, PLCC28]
Designator prefix IC

## T89C51CC02CA-TISIM (MPN: DIL40/SOIC28ZIFAWM-1; OC_FARNELL: unknown; OC_NEWARK: 89M9134), T89C51CC02UA-TISIM (MPN: DIL40/SOIC28ZIFAWM-1; OC_FARNELL: unknown; OC_NEWARK: 89M9134)  [SO28W]
1  VAREF  in
2  VAGND  in
3  VAVCC  in
4  P4.1/TXDC
5  P4.0/RXDC
6  P2.1
7  P3.7
8  P3.6
9  P3.5/T1
10  P3.4/T0
11  P3.3/!INT1
12  P3.2/!INT
13  P3.1/TXD
14  P3.0/RXD
15  XTAL2  in
16  XTAL1  in
17  VCC  pwr
18  VSS  pwr
19  RST  in
20  P2.0
21  P1.7/AN7
22  P1.6/AN6
23  P1.5/AN5
24  P1.4/AN4/CEX1
25  P1.3/AN3/CEX0
26  P1.2/AN2/ECI
27  P1.1/AN1/T2EX
28  P1.0/AN0/T2

## T89C51CC02CA-SISIM (MPN: DIL40/PLCC28ZIFAWM-1; OC_FARNELL: unknown; OC_NEWARK: 89M9105), T89C51CC02UA-SISIM (MPN: DIL40/PLCC28ZIFAWM-1; OC_FARNELL: unknown; OC_NEWARK: 89M9105)  [PLCC28]
Pads as for SO28W

## T89C51CC02CA-RATIM (OC_FARNELL: unknown; OC_NEWARK: unknown), T89C51CC02UA-RATIM (OC_FARNELL: unknown; OC_NEWARK: unknown)  [VQFP32]
1  P4.0/RXDC
2  P2.1
3  P3.7
4  P3.6
5  P3.5/T1
6  P3.4/T0
8  P3.3/!INT1
9  P3.2/!INT
10  P3.1/TXD
11  P3.0/RXD
13  XTAL2  in
14  XTAL1  in
15  VCC  pwr
16  VSS  pwr
17  RST  in
19  P2.0
20  P1.7/AN7
21  P1.6/AN6
22  P1.5/AN5
23  P1.4/AN4/CEX1
24  P1.3/AN3/CEX0
25  P1.2/AN2/ECI
26  P1.1/AN1/T2EX
27  P1.0/AN0/T2
28  VAREF  in
29  VAGND  in
31  VAVCC  in
32  P4.1/TXDC

## Footprint SO28W (pad centres in mm)
SMALL OUTLINE INTEGRATED CIRCUIT wide body 7.5 mm/JEDEC MO-119AB Source: http://www.atmel.com/dyn/resources/prod_documents/doc4126.pdf
smd 0.6 x 2.2: 1 -8.255,-4.6; 2 -6.985,-4.6; 3 -5.715,-4.6; 4 -4.445,-4.6; 5 -3.175,-4.6; 6 -1.905,-4.6; 7 -0.635,-4.6; 8 0.635,-4.6; 9 1.905,-4.6; 10 3.175,-4.6; 11 4.445,-4.6; 12 5.715,-4.6; 13 6.985,-4.6; 14 8.255,-4.6; 15 8.255,4.6; 16 6.985,4.6; 17 5.715,4.6; 18 4.445,4.6; 19 3.175,4.6; 20 1.905,4.6; 21 0.635,4.6; 22 -0.635,4.6; 23 -1.905,4.6; 24 -3.175,4.6; 25 -4.445,4.6; 26 -5.715,4.6; 27 -6.985,4.6; 28 -8.255,4.6

## Footprint PLCC28 (pad centres in mm)
PLASTIC LEADED CHIP CARRIER Source: http://www.atmel.com/dyn/resources/prod_documents/doc4126.pdf
smd 0.6 x 2: 1 0,5.6; 2 -1.27,5.6; 3 -2.54,5.6; 4 -3.81,5.6; 12 -3.81,-5.6; 13 -2.54,-5.6; 14 -1.27,-5.6; 15 0,-5.6; 16 1.27,-5.6; 17 2.54,-5.6; 18 3.81,-5.6; 26 3.81,5.6; 27 2.54,5.6; 28 1.27,5.6
smd 2 x 0.6: 5 -5.6,3.81; 6 -5.6,2.54; 7 -5.6,1.27; 8 -5.6,0; 9 -5.6,-1.27; 10 -5.6,-2.54; 11 -5.6,-3.81; 19 5.6,-3.81; 20 5.6,-2.54; 21 5.6,-1.27; 22 5.6,0; 23 5.6,1.27; 24 5.6,2.54; 25 5.6,3.81

## Footprint VQFP32 (pad centres in mm)
Quad Flat Pack Source: http://www.atmel.com/dyn/resources/prod_documents/doc4126.pdf
smd 1 x 0.45: 1 -4.15,2.8; 2 -4.15,2; 3 -4.15,1.2; 4 -4.15,0.4; 5 -4.15,-0.4; 6 -4.15,-1.2; 7 -4.15,-2; 8 -4.15,-2.8; 17 4.15,-2.8; 18 4.15,-2; 19 4.15,-1.2; 20 4.15,-0.4; 21 4.15,0.4; 22 4.15,1.2; 23 4.15,2; 24 4.15,2.8
smd 0.45 x 1: 9 -2.8,-4.15; 10 -2,-4.15; 11 -1.2,-4.15; 12 -0.4,-4.15; 13 0.4,-4.15; 14 1.2,-4.15; 15 2,-4.15; 16 2.8,-4.15; 25 2.8,4.15; 26 2,4.15; 27 1.2,4.15; 28 0.4,4.15; 29 -0.4,4.15; 30 -1.2,4.15; 31 -2,4.15; 32 -2.8,4.15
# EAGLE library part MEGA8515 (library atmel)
MICROCONTROLLER 8 Kbytes FLASH 512 bytes SRAM 512 bytes EEPROM USART 8-channel 10 bit ADC Source: avr.lbr

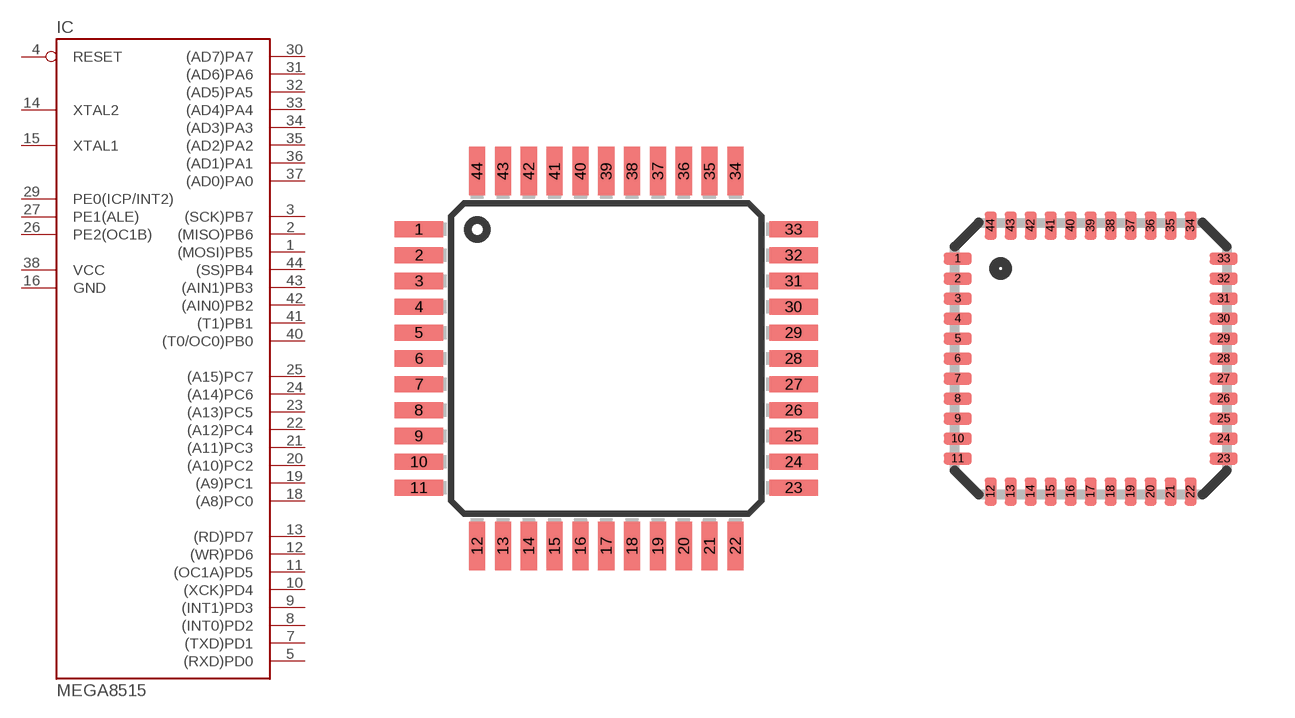
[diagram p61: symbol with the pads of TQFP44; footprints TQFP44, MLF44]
Designator prefix IC

## MEGA8515-A (MPN: ATMEGA8515-16AU; OC_FARNELL: 9171410; OC_NEWARK: 01M6904)  [TQFP44]
1  (MOSI)PB5
2  (MISO)PB6
3  (SCK)PB7
4  RESET  in
5  (RXD)PD0
6  NC1  nc
7  (TXD)PD1
8  (INT0)PD2
9  (INT1)PD3
10  (XCK)PD4
11  (OC1A)PD5
12  (WR)PD6
13  (RD)PD7
14  XTAL2
15  XTAL1
16  GND  pwr
17  NC2  nc
18  (A8)PC0
19  (A9)PC1
20  (A10)PC2
21  (A11)PC3
22  (A12)PC4
23  (A13)PC5
24  (A14)PC6
25  (A15)PC7
26  PE2(OC1B)
27  PE1(ALE)
28  NC3  nc
29  PE0(ICP/INT2)
30  (AD7)PA7
31  (AD6)PA6
32  (AD5)PA5
33  (AD4)PA4
34  (AD3)PA3
35  (AD2)PA2
36  (AD1)PA1
37  (AD0)PA0
38  VCC  pwr
39  NC4  nc
40  (T0/OC0)PB0
41  (T1)PB1
42  (AIN0)PB2
43  (AIN1)PB3
44  (SS)PB4

## MEGA8515-M (OC_FARNELL: unknown; OC_NEWARK: unknown)  [MLF44]
Pads as for TQFP44

## MEGA8515-J (MPN: ATMEGA8515-16JU; OC_FARNELL: 1562625; OC_NEWARK: 94M6261)  [PLCC44]
1  NC1  nc
2  (T0/OC0)PB0
3  (T1)PB1
4  (AIN0)PB2
5  (AIN1)PB3
6  (SS)PB4
7  (MOSI)PB5
8  (MISO)PB6
9  (SCK)PB7
10  RESET  in
11  (RXD)PD0
12  NC2  nc
13  (TXD)PD1
14  (INT0)PD2
15  (INT1)PD3
16  (XCK)PD4
17  (OC1A)PD5
18  (WR)PD6
19  (RD)PD7
20  XTAL2
21  XTAL1
22  GND  pwr
23  NC3  nc
24  (A8)PC0
25  (A9)PC1
26  (A10)PC2
27  (A11)PC3
28  (A12)PC4
29  (A13)PC5
30  (A14)PC6
31  (A15)PC7
32  PE2(OC1B)
33  PE1(ALE)
34  NC4  nc
35  PE0(ICP/INT2)
36  (AD7)PA7
37  (AD6)PA6
38  (AD5)PA5
39  (AD4)PA4
40  (AD3)PA3
41  (AD2)PA2
42  (AD1)PA1
43  (AD0)PA0
44  VCC  pwr

## Footprint TQFP44 (pad centres in mm)
44-lead Thin Quad Flat Package
smd 1.5 x 0.5: 1 -5.8,4; 2 -5.8,3.2; 3 -5.8,2.4; 4 -5.8,1.6; 5 -5.8,0.8; 6 -5.8,0; 7 -5.8,-0.8; 8 -5.8,-1.6; 9 -5.8,-2.4; 10 -5.8,-3.2; 11 -5.8,-4; 23 5.8,-4; 24 5.8,-3.2; 25 5.8,-2.4; 26 5.8,-1.6; 27 5.8,-0.8; 28 5.8,0; 29 5.8,0.8; 30 5.8,1.6; 31 5.8,2.4; 32 5.8,3.2; 33 5.8,4
smd 0.5 x 1.5: 12 -4,-5.8; 13 -3.2,-5.8; 14 -2.4,-5.8; 15 -1.6,-5.8; 16 -0.8,-5.8; 17 0,-5.8; 18 0.8,-5.8; 19 1.6,-5.8; 20 2.4,-5.8; 21 3.2,-5.8; 22 4,-5.8; 34 4,5.8; 35 3.2,5.8; 36 2.4,5.8; 37 1.6,5.8; 38 0.8,5.8; 39 0,5.8; 40 -0.8,5.8; 41 -1.6,5.8; 42 -2.4,5.8; 43 -3.2,5.8; 44 -4,5.8

## Footprint MLF44 (pad centres in mm)
44M1 Micro Lead Frame package (MLF)
smd 0.7 x 0.3: 1 -3.325,2.5; 2 -3.325,2; 3 -3.325,1.5; 4 -3.325,1; 5 -3.325,0.5; 6 -3.325,0; 7 -3.325,-0.5; 8 -3.325,-1; 9 -3.325,-1.5; 10 -3.325,-2; 11 -3.325,-2.5; 23 3.325,-2.5; 24 3.325,-2; 25 3.325,-1.5; 26 3.325,-1; 27 3.325,-0.5; 28 3.325,0; 29 3.325,0.5; 30 3.325,1; 31 3.325,1.5; 32 3.325,2; 33 3.325,2.5
smd 0.3 x 0.7: 12 -2.5,-3.325; 13 -2,-3.325; 14 -1.5,-3.325; 15 -1,-3.325; 16 -0.5,-3.325; 17 0,-3.325; 18 0.5,-3.325; 19 1,-3.325; 20 1.5,-3.325; 21 2,-3.325; 22 2.5,-3.325; 34 2.5,3.325; 35 2,3.325; 36 1.5,3.325; 37 1,3.325; 38 0.5,3.325; 39 0,3.325; 40 -0.5,3.325; 41 -1,3.325; 42 -1.5,3.325; 43 -2,3.325; 44 -2.5,3.325

## Footprint PLCC44 (pad centres in mm)
Plastic J-Leaded Chip Carrier
smd 1.8 x 0.76: 1 -7.86,0; 2 -7.86,-1.27; 3 -7.86,-2.54; 4 -7.86,-3.81; 5 -7.86,-5.08; 6 -7.86,-6.35; 18 7.86,-6.35; 19 7.86,-5.08; 20 7.86,-3.81; 21 7.86,-2.54; 22 7.86,-1.27; 23 7.86,0; 24 7.86,1.27; 25 7.86,2.54; 26 7.86,3.81; 27 7.86,5.08; 28 7.86,6.35; 40 -7.86,6.35; 41 -7.86,5.08; 42 -7.86,3.81; 43 -7.86,2.54; 44 -7.86,1.27
smd 0.76 x 1.8: 7 -6.35,-7.86; 8 -5.08,-7.86; 9 -3.81,-7.86; 10 -2.54,-7.86; 11 -1.27,-7.86; 12 0,-7.86; 13 1.27,-7.86; 14 2.54,-7.86; 15 3.81,-7.86; 16 5.08,-7.86; 17 6.35,-7.86; 29 6.35,7.86; 30 5.08,7.86; 31 3.81,7.86; 32 2.54,7.86; 33 1.27,7.86; 34 0,7.86; 35 -1.27,7.86; 36 -2.54,7.86; 37 -3.81,7.86; 38 -5.08,7.86; 39 -6.35,7.86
